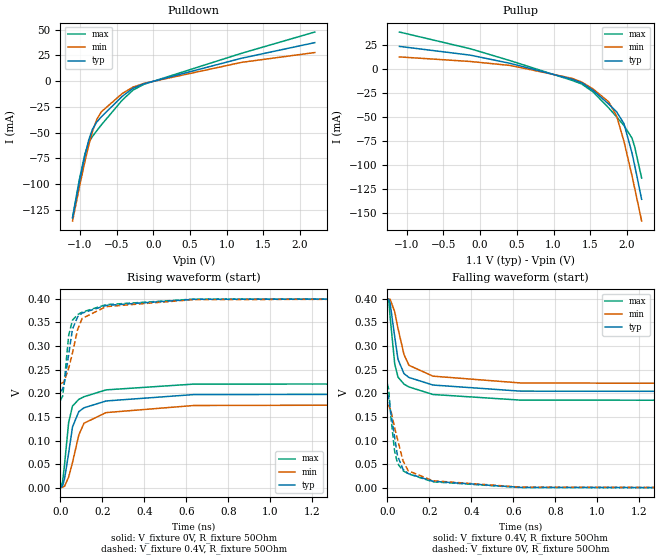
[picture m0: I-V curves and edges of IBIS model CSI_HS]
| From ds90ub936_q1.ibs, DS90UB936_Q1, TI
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|   CSI_HS
[Model]   CSI_HS
Model_type   Output
Polarity   Non-Inverting
Vmeas = 0.2
Vref = 0.2
Cref = 1pF
Rref = 50
|   typ   min   max
C_comp   3.509e-13   3.274e-13   3.913e-13
[Voltage Range]   1.1   1.045   1.155
[Temperature Range]   27   125   -40
[Pullup Reference]   1.1   1.045   1.155
[Pulldown Reference]   0   0   -0
[Power Clamp Reference]   1.1   1.045   1.155
[GND Clamp Reference]   0   0   0
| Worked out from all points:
|   slope of the pulldown table from 0 to 0.165 V, typ, clamps not added: 51.9 ohm
|   slope of the pullup table from 0 to 0.165 V, typ, clamps not added: 65.3 ohm
|   falling waveform, V_fixture 0.4V, R_fixture 50Ohm: 20-80 % time 55.8ps typ, 70.1ps min, 44.9ps max; typ from 0.4 V to 0.204 V
|   rising waveform, V_fixture 0V, R_fixture 50Ohm: 20-80 % time 55.5ps typ, 72.7ps min, 43.1ps max; typ from 0 V to 0.198 V
|   rising waveform, V_fixture 0.4V, R_fixture 50Ohm: 20-80 % time 53.5ps typ, 71.6ps min, 41.4ps max; typ from 0.204 V to 0.4 V
|   falling waveform, V_fixture 0V, R_fixture 50Ohm: 20-80 % time 57.4ps typ, 72.8ps min, 45.8ps max; typ from 0.198 V to 0 V
[Pulldown]
|   Voltage   I(typ)   I(min)   I(max)
-1.1V     -133.1mA   -136.1mA   -132.4mA
-1.008V   -98.27mA   -103.4mA   -95.88mA
-931.7mV  -72.32mA   -78.2mA    -70.83mA
-878.9mV  -57.13mA   -62.19mA   -59.69mA
-829.4mV  -46.84mA   -49.1mA    -53.81mA
-770mV    -39.76mA   -37.26mA   -48.21mA
-707.3mV  -34.65mA   -29.77mA   -42.52mA
-423.5mV  -14.77mA   -12.06mA   -18.47mA
-275mV    -6.866mA   -5.709mA   -8.616mA
-123.2mV  -2.428mA   -2.088mA   -2.913mA
1.203V    22.33mA    18.32mA    27.17mA
2.2V      37.53mA    27.87mA    47.84mA
[Pullup]
|   Voltage   I(typ)   I(min)   I(max)
-1.1V     23.2mA     12.25mA    38.14mA
-133.1mV  14.06mA    7.492mA    20.72mA
411.4mV   5.508mA    3.337mA    8.305mA
1.25V     -10.93mA   -9.981mA   -12.11mA
1.385V    -14.76mA   -13.94mA   -15.97mA
1.54V     -22.65mA   -21.22mA   -24.33mA
1.751V    -36.83mA   -34.45mA   -40.8mA
1.86V     -45.01mA   -49.44mA   -50.25mA
1.959V    -57.19mA   -75.55mA   -59.12mA
2.068V    -87.64mA   -111.2mA   -72.14mA
2.104V    -100.2mA   -123.9mA   -80.85mA
2.2V      -135.9mA   -158.5mA   -113.8mA
[Ramp]
R_load = 50
|   typ   min   max
dV/dt_r   0.119002/5.55154e-11   0.105474/7.2631e-11   0.132077/4.31074e-11
dV/dt_f   0.117699/5.57679e-11   0.107612/7.0065e-11   0.128903/4.49202e-11
[Falling Waveform]
V_fixture = 0.4V
V_fixture_min = 0.4V
V_fixture_max = 0.4V
R_fixture = 50Ohm
C_fixture = 0F
|   Time   V(typ)   V(min)   V(max)
|   0   0.399984   0.399894   0.399996
|   1.20472e-10   0.400004   0.399908   0.400048
|   1.23636e-10   0.400005   0.399908   0.399435
|   1.2535e-10   0.400005   0.399909   0.397602
|   1.27327e-10   0.400005   0.399909   0.392472
|   1.29834e-10   0.400006   0.399909   0.380059
|   1.32951e-10   0.400006   0.39991   0.359496
|   1.33466e-10   0.399997   0.39991   0.356101
|   1.35348e-10   0.399965   0.39991   0.345211
|   1.37316e-10   0.399931   0.39991   0.335527
|   1.39595e-10   0.399891   0.39991   0.32617
|   1.45138e-10   0.399795   0.399911   0.306849
|   1.46694e-10   0.399769   0.399911   0.299577
|   1.46773e-10   0.39975   0.399911   0.299208
|   1.49625e-10   0.399063   0.399911   0.283006
|   1.507e-10   0.398804   0.399912   0.277485
|   1.50772e-10   0.398742   0.399912   0.277118
|   1.53447e-10   0.396415   0.399912   0.265872
|   1.53521e-10   0.396269   0.399912   0.265561
|   1.5587e-10   0.391658   0.399912   0.257917
|   1.56757e-10   0.389918   0.399912   0.25561
|   1.58093e-10   0.385433   0.399912   0.252135
|   1.60147e-10   0.37854   0.399913   0.247858
|   1.60801e-10   0.375832   0.399913   0.246497
|   1.62825e-10   0.36745   0.399913   0.243184
|   1.6386e-10   0.363266   0.399913   0.241491
|   1.65337e-10   0.357295   0.399913   0.239602
|   1.67364e-10   0.350047   0.399914   0.237008
|   1.6823e-10   0.346953   0.399914   0.236152
|   1.69048e-10   0.344443   0.399914   0.235342
|   1.7112e-10   0.338088   0.399852   0.233291
|   1.71542e-10   0.336966   0.39984   0.232874
|   1.73986e-10   0.330461   0.399767   0.231026
|   1.76523e-10   0.324244   0.399692   0.229107
|   1.78485e-10   0.319436   0.399634   0.227989
|   1.81176e-10   0.311827   0.399554   0.226454
|   1.82886e-10   0.305868   0.399503   0.225479
|   1.83342e-10   0.304279   0.39949   0.225286
|   1.86987e-10   0.29079   0.399382   0.223742
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0s        400mV      399.9mV    400mV
7.584ps   398.7mV    399.5mV    393.7mV
13.57ps   389.9mV    399mV      360.1mV
35.3ps    319.4mV    372.5mV    262.1mV
50.77ps   271.9mV    337.7mV    234.3mV
79.38ps   241.8mV    282.1mV    219.6mV
103.2ps   233.6mV    259.3mV    213.5mV
217.4ps   217.6mV    236.4mV    197.6mV
634.3ps   204.7mV    222mV      185.7mV
2.281ns   203.8mV    220.5mV    185.2mV
[Rising Waveform]
V_fixture = 0V
V_fixture_min = 0V
V_fixture_max = 0V
R_fixture = 50Ohm
C_fixture = 0F
|   Time   V(typ)   V(min)   V(max)
|   0   1.9484e-05   8.14148e-05   6.66717e-06
|   1.15219e-10   -0.000105023   1.05096e-05   -0.000240685
|   1.17817e-10   -0.00010783   8.91084e-06   0.000128634
|   1.2223e-10   -0.000112598   6.19544e-06   0.00229223
|   1.23636e-10   -0.000114118   5.33011e-06   0.00319929
|   1.2535e-10   -0.00011597   4.27543e-06   0.00473506
|   1.27327e-10   -0.000118106   3.05885e-06   0.00768527
|   1.29834e-10   -0.000120816   1.51564e-06   0.0136966
|   1.31765e-10   -0.000122903   3.27335e-07   0.0198714
|   1.33466e-10   -0.00012474   -7.19126e-07   0.0261768
|   1.35348e-10   -0.000126774   -1.8775e-06   0.0339726
|   1.37316e-10   -0.000128901   -3.08857e-06   0.042783
|   1.38422e-10   -0.000130096   -3.76901e-06   0.0478844
|   1.39595e-10   1.57e-05   -4.49101e-06   0.0532974
|   1.41756e-10   0.000284265   -5.82098e-06   0.0631025
|   1.42762e-10   0.00040926   -6.43998e-06   0.0674439
|   1.43469e-10   0.000642796   -6.87472e-06   0.0704931
|   1.46773e-10   0.00173525   -8.90839e-06   0.0842313
|   1.48396e-10   0.00227174   -9.9071e-06   0.0916175
|   1.49625e-10   0.00267785   -1.06631e-05   0.0977685
|   1.507e-10   0.00303342   -1.1325e-05   0.103445
|   1.53447e-10   0.00472072   -1.30151e-05   0.117939
|   1.53521e-10   0.00480055   -1.30607e-05   0.11833
|   1.5587e-10   0.00733467   -1.45066e-05   0.129086
|   1.56757e-10   0.00829113   -1.50524e-05   0.132517
|   1.58093e-10   0.0104971   -1.58747e-05   0.137686
|   1.60147e-10   0.0138883   -1.71387e-05   0.144276
|   1.60801e-10   0.0152738   -1.75411e-05   0.146373
|   1.62825e-10   0.0195618   -1.87865e-05   0.151574
|   1.6386e-10   0.0220879   -1.94233e-05   0.154233
|   1.65337e-10   0.0256935   -2.03323e-05   0.157186
|   1.67364e-10   0.0311169   -2.15799e-05   0.161239
|   1.6823e-10   0.0334324   -2.21125e-05   0.162539
|   1.7112e-10   0.0416141   -2.38913e-05   0.166881
|   1.71542e-10   0.0428162   -2.41508e-05   0.167515
|   1.75052e-10   0.0528214   -2.63106e-05   0.171334
|   1.76523e-10   0.057017   9.03419e-05   0.172936
|   1.82155e-10   0.0730736   0.000536762   0.177221
|   1.82886e-10   0.0751563   0.000677102   0.177777
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0s        19.48uV    81.41uV    6.667uV
10.33ps   4.801mV    1.338mV    13.18mV
19.64ps   19.56mV    3.484mV    50.19mV
38.97ps   73.07mV    22.82mV    138.2mV
57.3ps    128.8mV    53.54mV    173mV
87.42ps   161.4mV    111.8mV    187.3mV
112.1ps   169.4mV    136.8mV    192.9mV
217.4ps   183.9mV    159.3mV    207.4mV
634.3ps   197.4mV    174.3mV    219.6mV
2.281ns   198.4mV    175.9mV    220.1mV
[Rising Waveform]
V_fixture = 0.4V
V_fixture_min = 0.4V
V_fixture_max = 0.4V
R_fixture = 50Ohm
C_fixture = 0F
|   Time   V(typ)   V(min)   V(max)
|   0   0.20382   0.220541   0.185158
|   1.15219e-10   0.203693   0.220464   0.184912
|   1.17817e-10   0.20369   0.220462   0.185376
|   1.20472e-10   0.203687   0.220461   0.186758
|   1.2223e-10   0.203685   0.220459   0.187919
|   1.23636e-10   0.203683   0.220458   0.188883
|   1.27327e-10   0.203679   0.220456   0.191516
|   1.29834e-10   0.203677   0.220454   0.194289
|   1.31765e-10   0.203674   0.220453   0.198302
|   1.33466e-10   0.203673   0.220452   0.204092
|   1.35348e-10   0.20367   0.220451   0.212716
|   1.37316e-10   0.203668   0.220449   0.223092
|   1.38422e-10   0.203667   0.220449   0.228895
|   1.41756e-10   0.204205   0.220446   0.246396
|   1.42762e-10   0.204368   0.220446   0.251135
|   1.43469e-10   0.204666   0.220445   0.254463
|   1.48396e-10   0.206745   0.220442   0.27542
|   1.49625e-10   0.207263   0.220441   0.281443
|   1.507e-10   0.207717   0.22044   0.287236
|   1.53447e-10   0.209225   0.220439   0.302027
|   1.53521e-10   0.209285   0.220438   0.302425
|   1.5587e-10   0.211197   0.220437   0.313151
|   1.56757e-10   0.211918   0.220436   0.316499
|   1.58093e-10   0.213913   0.220435   0.321542
|   1.60147e-10   0.21698   0.220434   0.327877
|   1.60801e-10   0.218493   0.220434   0.329894
|   1.62825e-10   0.223175   0.220432   0.334834
|   1.6386e-10   0.226136   0.220432   0.33736
|   1.65337e-10   0.230363   0.220431   0.340135
|   1.67364e-10   0.23672   0.220429   0.343946
|   1.6823e-10   0.239434   0.220429   0.345158
|   1.71542e-10   0.249947   0.220426   0.349796
|   1.73986e-10   0.257705   0.220425   0.352262
|   1.75052e-10   0.260831   0.220424   0.353336
|   1.76523e-10   0.26515   0.220602   0.354821
|   1.82155e-10   0.281679   0.221284   0.358788
|   1.82886e-10   0.283823   0.221503   0.359303
|   1.83342e-10   0.285161   0.22164   0.359521
|   1.85444e-10   0.292262   0.22227   0.360528
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0s        203.8mV    220.5mV    185.2mV
10.33ps   209.3mV    222.5mV    194.1mV
16.96ps   217mV      224.8mV    217.4mV
38.97ps   281.7mV    252.6mV    322mV
57.3ps    336mV      285.7mV    354.9mV
81.91ps   361.9mV    335.2mV    366.6mV
103.2ps   369.9mV    358.5mV    371.9mV
217.4ps   386.1mV    383.6mV    387.8mV
634.3ps   399.1mV    398.4mV    399.5mV
2.281ns   400mV      399.9mV    400mV
[Falling Waveform]
V_fixture = 0V
V_fixture_min = 0V
V_fixture_max = 0V
R_fixture = 50Ohm
C_fixture = 0F
0s        198.4mV    175.9mV    220.1mV
6.163ps   190.8mV    174mV      209.5mV
16.96ps   158.3mV    163.7mV    150.2mV
34.25ps   108.8mV    128.1mV    78.8mV
48.39ps   67.9mV     103.1mV    51.73mV
74.58ps   39.48mV    57.49mV    36.48mV
99.6ps    30.24mV    36.14mV    29.69mV
217.4ps   13.84mV    15.02mV    12.77mV
634.3ps   981.3uV    1.539mV    632uV
2.281ns   19.68uV    81.37uV    6.668uV
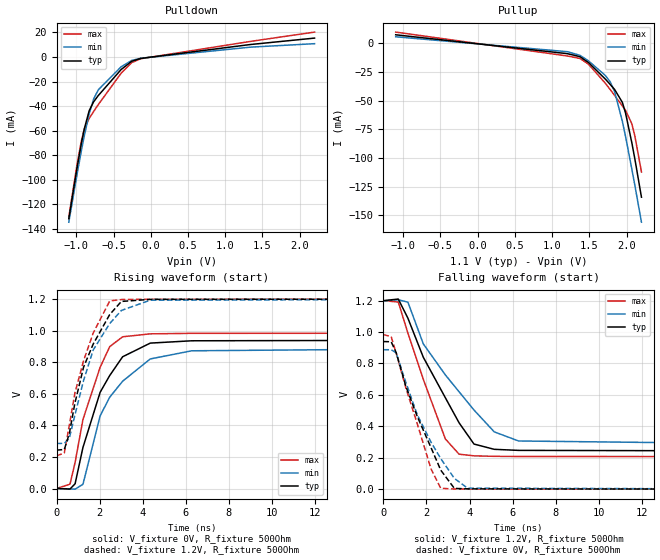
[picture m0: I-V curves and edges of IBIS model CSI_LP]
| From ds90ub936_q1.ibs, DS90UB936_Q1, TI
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|   CSI_LP
[Model]   CSI_LP
Model_type   Output
Polarity   Non-Inverting
Vmeas = 0.5
Vref = 0
Cref = 1pF
Rref = 100000
|   typ   min   max
C_comp   3.509e-13   3.274e-13   3.913e-13
[Voltage Range]   1.1   1.045   1.155
[Temperature Range]   27   125   -40
[Pullup Reference]   1.1   1.045   1.155
[Pulldown Reference]   -0   0   -0
[Power Clamp Reference]   1.1   1.045   1.155
[GND Clamp Reference]   0   0   0
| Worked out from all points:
|   slope of the pulldown table from 0 to 0.165 V, typ, clamps not added: 126 ohm
|   slope of the pullup table from 0 to 0.165 V, typ, clamps not added: 139 ohm
|   falling waveform, V_fixture 1.2V, R_fixture 500Ohm: 20-80 % time 2.14ns typ, 2.83ns min, 1.53ns max; typ from 1.2 V to 0.243 V
|   rising waveform, V_fixture 0V, R_fixture 500Ohm: 20-80 % time 1.51ns typ, 1.77ns min, 1.18ns max; typ from 0 V to 0.94 V
|   rising waveform, V_fixture 1.2V, R_fixture 500Ohm: 20-80 % time 1.35ns typ, 1.44ns min, 1.15ns max; typ from 0.243 V to 1.2 V
|   falling waveform, V_fixture 0V, R_fixture 500Ohm: 20-80 % time 1.61ns typ, 1.76ns min, 1.32ns max; typ from 0.94 V to 0 V
[Pulldown]
|   Voltage   I(typ)   I(min)   I(max)
-1.1V     -131.6mA   -134.4mA   -130mA
-984.5mV  -88.33mA   -93.74mA   -85.47mA
-928.4mV  -69.39mA   -75.29mA   -67.39mA
-892.1mV  -58.5mA    -64.08mA   -58.74mA
-826.1mV  -43.61mA   -46.11mA   -49.9mA
-766.7mV  -36.42mA   -34.17mA   -44.33mA
-704mV    -31.32mA   -26.65mA   -38.69mA
-397.1mV  -10.14mA   -7.924mA   -13.13mA
-255.2mV  -3.45mA    -2.772mA   -4.544mA
-133.1mV  -1.132mA   -966.8uA   -1.362mA
1.342V    10.2mA     8.051mA    12.73mA
2.2V      15.4mA     10.86mA    20.29mA
[Pullup]
|   Voltage   I(typ)   I(min)   I(max)
-1.1V     7.43mA     5.697mA    9.786mA
1.207V    -9.043mA   -7.312mA   -11.07mA
1.375V    -11.69mA   -10.51mA   -13.23mA
1.487V    -16.68mA   -15.2mA    -18.1mA
1.712V    -31.01mA   -27.85mA   -34.6mA
1.781V    -35.92mA   -33.61mA   -40.42mA
1.84V     -40.31mA   -42.29mA   -45.52mA
1.943V    -51.44mA   -67.87mA   -54.51mA
1.986V    -60.7mA    -81.11mA   -58.44mA
2.071V    -86.84mA   -109.8mA   -70.21mA
2.111V    -100.7mA   -123.7mA   -80.63mA
2.2V      -134.2mA   -156mA     -112.2mA
[Ramp]
R_load = 500
|   typ   min   max
dV/dt_r   0.563627/1.50879e-09   0.532177/1.7689e-09   0.590261/1.18088e-09
dV/dt_f   0.574053/2.14179e-09   0.547641/2.82676e-09   0.59558/1.52734e-09
[Falling Waveform]
V_fixture = 1.2V
V_fixture_min = 1.2V
V_fixture_max = 1.2V
R_fixture = 500Ohm
C_fixture = 0F
|   Time   V(typ)   V(min)   V(max)
0s        1.2V       1.198V     1.2V
691.4ps   1.21V      1.206V     1.191V
1.138ns   1.088V     1.19V      992.9mV
1.852ns   839.7mV    924.8mV    699.2mV
2.876ns   581.8mV    727.2mV    319.7mV
3.513ns   422.4mV    619.8mV    222.6mV
4.206ns   287.1mV    503.7mV    212.1mV
5.145ns   253.7mV    364.8mV    209mV
6.275ns   246.9mV    306.7mV    208mV
20ns      242.9mV    285.5mV    207.1mV
[Rising Waveform]
V_fixture = 0V
V_fixture_min = 0V
V_fixture_max = 0V
R_fixture = 500Ohm
C_fixture = 0F
|   Time   V(typ)   V(min)   V(max)
0s        123.3uV    459.5uV    46.35uV
625.4ps   -3.433mV   -2.62mV    27.35mV
863.1ps   30.29mV    -4.212mV   165.8mV
1.226ns   259.8mV    26.63mV    437mV
2.025ns   609.7mV    460.4mV    768.1mV
2.469ns   715.7mV    578.2mV    898.6mV
3.067ns   834.3mV    679.5mV    961mV
4.351ns   921mV      820.7mV    979.7mV
6.275ns   935.7mV    872.3mV    982.9mV
20ns      939.5mV    887.4mV    983.8mV
[Rising Waveform]
V_fixture = 1.2V
V_fixture_min = 1.2V
V_fixture_max = 1.2V
R_fixture = 500Ohm
C_fixture = 0F
|   Time   V(typ)   V(min)   V(max)
0s        242.9mV    285.5mV    207.1mV
361.4ps   247.2mV    285.8mV    224.5mV
590.7ps   345.7mV    317.9mV    399.3mV
850.6ps   539.3mV    463.2mV    603.5mV
1.255ns   768.7mV    683.7mV    809mV
1.703ns   915.1mV    877.6mV    985mV
2.469ns   1.102V     1.045V     1.188V
3.011ns   1.185V     1.128V     1.197V
4.351ns   1.198V     1.193V     1.199V
20ns      1.2V       1.198V     1.2V
[Falling Waveform]
|Gnd
V_fixture = 0V
V_fixture_min = 0V
V_fixture_max = 0V
R_fixture = 500Ohm
C_fixture = 0F
|   Time   V(typ)   V(min)   V(max)
0s        939.5mV    887.4mV    983.8mV
361.4ps   938.2mV    887.8mV    970.9mV
590.7ps   870.2mV    867.9mV    866.3mV
1.046ns   653.3mV    678.5mV    643.2mV
1.57ns    463.2mV    474.2mV    417.2mV
2.213ns   263.8mV    298.7mV    127.9mV
2.662ns   121.1mV    194.6mV    5.397mV
3.295ns   4.892mV    68.42mV    1.302mV
3.908ns   1.911mV    6.441mV    869.5uV
20ns      123.3uV    459.5uV    46.34uV
